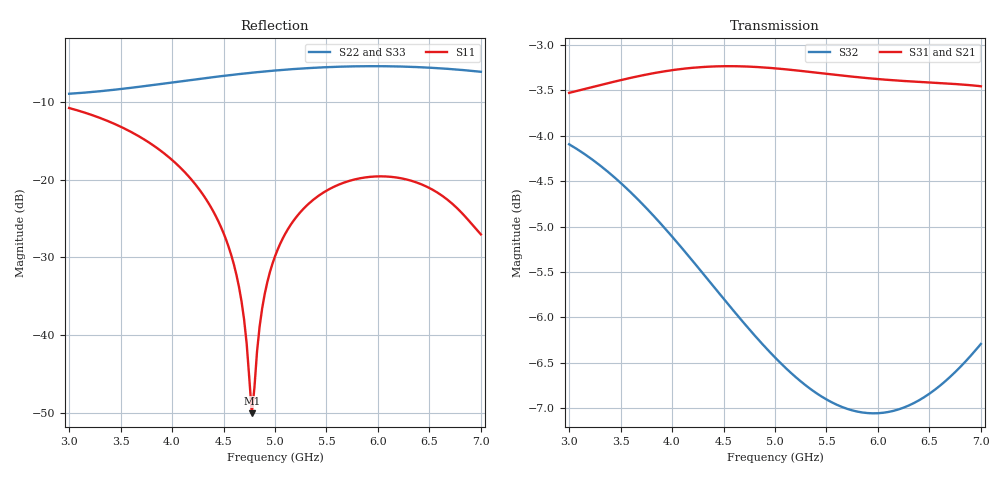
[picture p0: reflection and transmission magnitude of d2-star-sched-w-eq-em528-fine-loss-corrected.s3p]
! yapnr Order 0 prediction d2-star-sched-w-eq-em528-fine: predictions/D2/variants/d2-star-sched-w-eq-em528/fine.s3p, loss-corrected
! substrate W-eq-em528; coupon model OSHPARK-4L-EM528; correction: ratio (port line)
! |S21|, |S31| (and S12, S13) scaled, phases kept; 50 ohm, e^(+jwt)
# GHz S RI R 50
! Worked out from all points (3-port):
!   161 points, 3 GHz to 7 GHz, reference 50 ohm
!   strongest paths, dB at 3 GHz, 4 GHz, 5 GHz, 6 GHz, 7 GHz:
!     S31: -3.5, -3.3, -3.3, -3.4, -3.5
!     S21: -3.5, -3.3, -3.3, -3.4, -3.5
!     S32: -4.1, -5.1, -6.4, -7.1, -6.3
!   lowest |S11| = -50.0 dB at 4.775 GHz (marker M1), VSWR 1.01, Z = 49.8 + j0.269 ohm
!   |S11| at or under -10 dB: start of sweep to end of sweep
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3  -0.107 0.2683  -0.3898 -0.5404  -0.3898 -0.5404
   -0.3898 -0.5399  0.3155 0.1666  -0.6052 -0.1519
   -0.3898 -0.5399  -0.6052 -0.1519  0.3155 0.1666
3.825  0.0279 0.1625  -0.653 -0.1998  -0.653 -0.1998
       -0.6528 -0.2003  0.3628 -0.1844  -0.4819 0.3038
       -0.6528 -0.2003  -0.4819 0.3038  0.3628 -0.1844
4.375  0.0346 0.0574  -0.6799 0.1043  -0.6799 0.1043
       -0.6807 0.1032  0.2338 -0.3895  -0.2523 0.4588
       -0.6807 0.1032  -0.2523 0.4588  0.2338 -0.3895
4.65  0.0122 0.0164  -0.6389 0.2545  -0.6389 0.2545
      -0.6404 0.2534  0.1338 -0.4583  -0.1312 0.4839
      -0.6404 0.2534  -0.1312 0.4839  0.1338 -0.4583
4.775  -0.00162 0.0027  -0.6087 0.3187  -0.6087 0.3187
       -0.6106 0.3178  0.0833 -0.4801  -0.0784 0.4856
       -0.6106 0.3178  -0.0784 0.4856  0.0833 -0.4801
4.875  -0.0137 -0.00577  -0.5797 0.3674  -0.5797 0.3674
       -0.5819 0.3667  0.0414 -0.493  -0.0377 0.4833
       -0.5819 0.3667  -0.0377 0.4833  0.0414 -0.493
5  -0.0293 -0.0131  -0.5379 0.4245  -0.5379 0.4245
   -0.5404 0.4241  -0.0122 -0.5032  0.011 0.4764
   -0.5404 0.4241  0.011 0.4764  -0.0122 -0.5032
5.35  -0.0705 -0.0157  -0.3928 0.5567  -0.3928 0.5567
      -0.3956 0.5577  -0.1626 -0.497  0.1332 0.4378
      -0.3956 0.5577  0.1332 0.4378  -0.1626 -0.497
5.9  -0.1027 0.0156  -0.1091 0.6664  -0.1091 0.6664
     -0.1106 0.6694  -0.3661 -0.3925  0.2866 0.3393
     -0.1106 0.6694  0.2866 0.3393  -0.3661 -0.3925
7  -0.0434 0.00987  0.4633 0.4825  0.4633 0.4825
   0.4666 0.4829  -0.494 -0.00498  0.4841 0.0232
   0.4666 0.4829  0.4841 0.0232  -0.494 -0.00498
